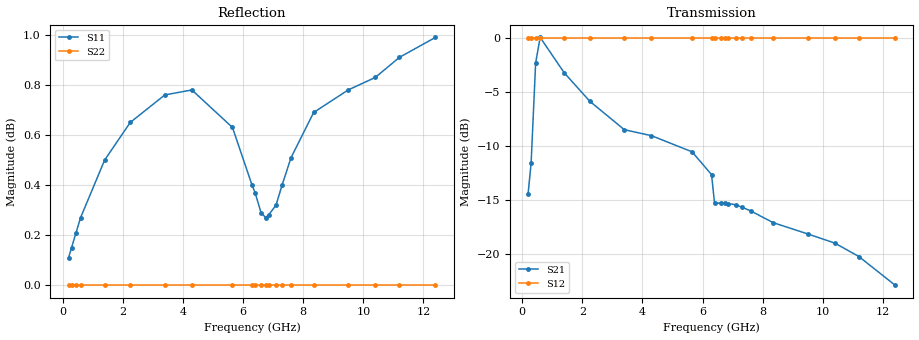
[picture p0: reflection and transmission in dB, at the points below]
# hz S db R 100
! AFE7900 - TX Channel A, DSA = 40dB, Fs = 11.79648 GHz
! 4/8/20
! Port 1 - SE representation of DAC differential output
! Port 2 - DAC analogoutput
! freq  dbS11  angS11
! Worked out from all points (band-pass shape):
!   245 points, 200 MHz to 12.4 GHz, reference 100 ohm
!   highest |S21| = 0.02 dB at 600 MHz (marker M1); lowest = -22.9 dB at 12.4 GHz (marker M2)
!   |S21| within 3 dB of the highest: 436.8 MHz to 1.303 GHz (865.9 MHz wide, 99.6 % of centre)
!   lowest |S11| = 0.1 dB at 200 MHz (marker M3)
!   |S11| at or under -10 dB: nowhere
!   |S22| runs from 0.0 to 0.0 dB; largest |S21 - S12| = 0.93
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2e8  0.11 -78.0  -14.42 0.0  0.00 0.0  0.00 0.0
3e8  0.15 -86.9  -11.56 0.0  0.00 0.0  0.00 0.0
4.5e8  0.21 -97.1  -2.34 0.0  0.00 0.0  0.00 0.0
6e8  0.27 -104.4  0.02 0.0  0.00 0.0  0.00 0.0
1.4e9  0.50 -131.3  -3.25 0.0  0.00 0.0  0.00 0.0
2.25e9  0.65 -154.7  -5.88 0.0  0.00 0.0  0.00 0.0
3.4e9  0.76 178.6  -8.51 0.0  0.00 0.0  0.00 0.0
4.3e9  0.78 165.8  -9.06 0.0  0.00 0.0  0.00 0.0
5.65e9  0.63 146.8  -10.55 0.0  0.00 0.0  0.00 0.0
6.3e9  0.40 117.7  -12.66 0.0  0.00 0.0  0.00 0.0
6.4e9  0.37 109.1  -15.31 0.0  0.00 0.0  0.00 0.0
6.6e9  0.29 88.8  -15.28 0.0  0.00 0.0  0.00 0.0
6.75e9  0.27 64.3  -15.31 0.0  0.00 0.0  0.00 0.0
6.85e9  0.28 45.1  -15.33 0.0  0.00 0.0  0.00 0.0
7.1e9  0.32 9.7  -15.44 0.0  0.00 0.0  0.00 0.0
7.3e9  0.40 -10.2  -15.66 0.0  0.00 0.0  0.00 0.0
7.6e9  0.51 -27.1  -16.01 0.0  0.00 0.0  0.00 0.0
8.35e9  0.69 -52.5  -17.10 0.0  0.00 0.0  0.00 0.0
9.5e9  0.78 -86.3  -18.14 0.0  0.00 0.0  0.00 0.0
1.04e10  0.83 -120.1  -18.99 0.0  0.00 0.0  0.00 0.0
1.12e10  0.91 -144.9  -20.23 0.0  0.00 0.0  0.00 0.0
1.24e10  0.99 -157.9  -22.87 0.0  0.00 0.0  0.00 0.0
